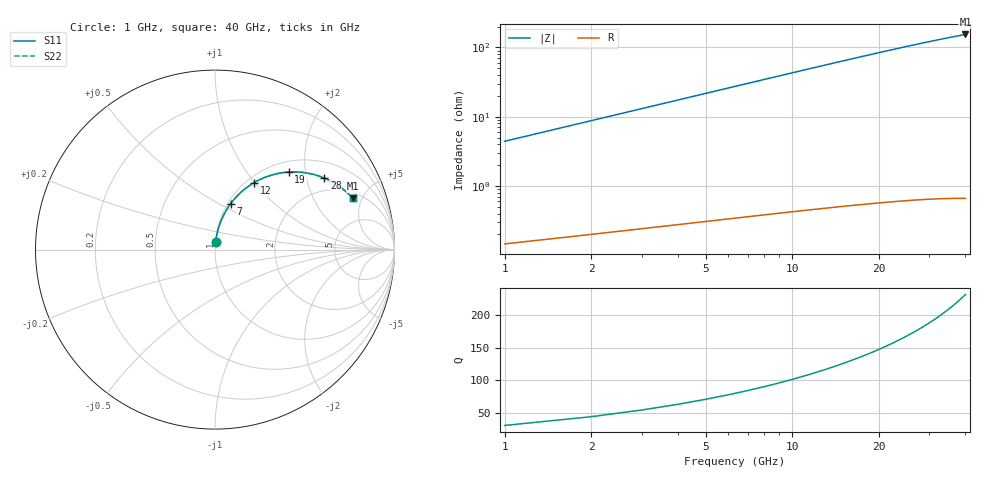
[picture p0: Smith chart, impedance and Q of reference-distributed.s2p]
! circuitRF wBond ? one port per TERMINAL, all referenced to the ground plane at z = 0, which is this file's common reference node.
! 1 array(s), 1 wire(s). Reference impedance 50 ohm, uniform and real.
! Port[1] = G1.i
! Port[2] = G1.o
! Model: distributed (MoM), 24 segments per wire, 25 current unknowns.
! Includes the wires' capacitance to the reference plane and between arrays.
! Medium: air (er = 1) ? no overmold.
# GHz S RI R 50
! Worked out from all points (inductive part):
!   40 points, 1 GHz to 40 GHz, reference 50 ohm
!   read as one part in series: L = 698 pH near 1 GHz
!   highest Q = 232 at 40 GHz (marker M1), where L = 613 pH
!   S11 on the Smith chart (normalised r, x): 1 GHz: 1.00, +0.08; 7 GHz: 1.03, +0.57; 12 GHz: 1.08, +0.99; 19 GHz: 1.21, +1.62; 28 GHz: 1.51, +2.56; 40 GHz: 2.42, +4.21
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1  0.00339 0.0411  0.9966 -0.047  0.9966 -0.047  0.00339 0.0411
2  0.00956 0.0808  0.9904 -0.0927  0.9904 -0.0927  0.00956 0.0808
3  0.0191 0.1194  0.9807 -0.1372  0.9807 -0.1372  0.0191 0.1194
4  0.032 0.1566  0.9678 -0.1803  0.9678 -0.1803  0.032 0.1566
5  0.0478 0.192  0.9518 -0.2217  0.9518 -0.2217  0.0478 0.192
6  0.0664 0.2253  0.933 -0.261  0.933 -0.261  0.0664 0.2253
7  0.0874 0.2563  0.9117 -0.2979  0.9117 -0.2979  0.0874 0.2563
8  0.1105 0.2848  0.8884 -0.3324  0.8884 -0.3324  0.1105 0.2848
9  0.1352 0.3107  0.8633 -0.3643  0.8633 -0.3643  0.1352 0.3107
10  0.1614 0.334  0.8368 -0.3935  0.8368 -0.3935  0.1614 0.334
12  0.2164 0.3724  0.781 -0.4439  0.781 -0.4439  0.2164 0.3724
14  0.2732 0.4005  0.7233 -0.484  0.7233 -0.484  0.2732 0.4005
16  0.3296 0.4192  0.6658 -0.5147  0.6658 -0.5147  0.3296 0.4192
19  0.4108 0.432  0.5827 -0.5458  0.5827 -0.5458  0.4108 0.432
21  0.4611 0.4323  0.5309 -0.5583  0.5309 -0.5583  0.4611 0.4323
24  0.53 0.4233  0.4595 -0.5677  0.4595 -0.5677  0.53 0.4233
27  0.5904 0.4059  0.3962 -0.5689  0.3962 -0.5689  0.5904 0.4059
28  0.6087 0.3987  0.3768 -0.5679  0.3768 -0.5679  0.6087 0.3987
31  0.6584 0.3741  0.3237 -0.5623  0.3237 -0.5623  0.6584 0.3741
34  0.7009 0.3464  0.2773 -0.5537  0.2773 -0.5537  0.7009 0.3464
37  0.7371 0.3168  0.2368 -0.5435  0.2368 -0.5435  0.7371 0.3168
40  0.7678 0.2862  0.2013 -0.5326  0.2013 -0.5326  0.7678 0.2862
